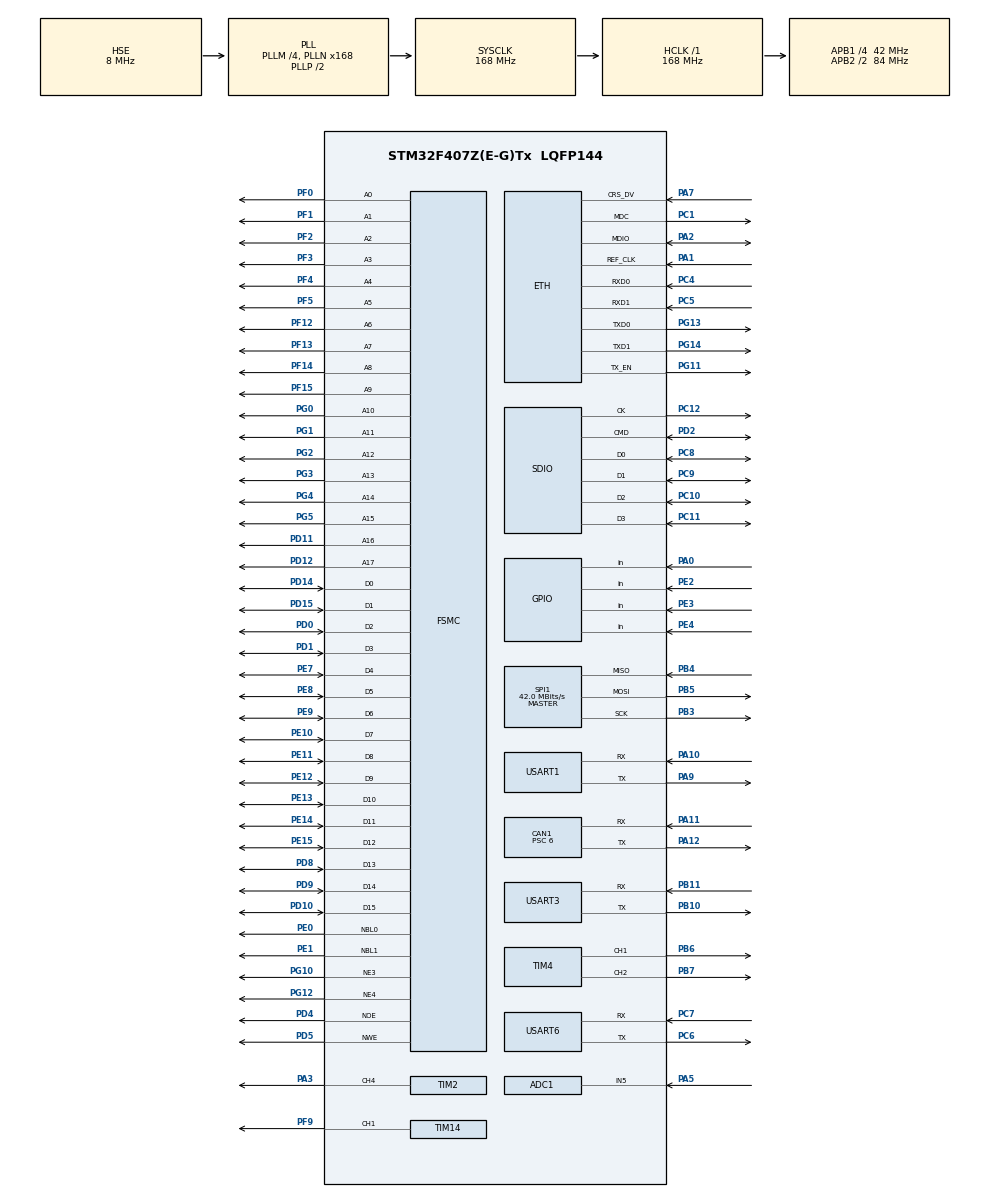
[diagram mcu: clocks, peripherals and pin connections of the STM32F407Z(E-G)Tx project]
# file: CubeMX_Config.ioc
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ADC1.Channel-0\#ChannelRegularConversion=ADC_CHANNEL_5
ADC1.NbrOfConversionFlag=1
ADC1.Rank-0\#ChannelRegularConversion=1
ADC1.SamplingTime-0\#ChannelRegularConversion=ADC_SAMPLETIME_3CYCLES
ADC1.master=1
CAN1.BS1=CAN_BS1_7TQ
CAN1.BS2=CAN_BS2_6TQ
CAN1.CalculateTimeQuantum=142.85714285714286
CAN1.Prescaler=6
ETH.MediaInterface=ETH_MEDIA_INTERFACE_RMII
FSMC.AddressSetupTime3=0
FSMC.BusTurnAroundDuration3=0
FSMC.BusTurnAroundDuration4=0
FSMC.DataSetupTime3=8
FSMC.DataSetupTime4=24
FSMC.ExtendedAddressSetupTime3=0
FSMC.ExtendedAddressSetupTime4=8
FSMC.ExtendedBusTurnAroundDuration3=0
FSMC.ExtendedBusTurnAroundDuration4=0
FSMC.ExtendedDataSetupTime3=8
FSMC.ExtendedDataSetupTime4=8
FSMC.ExtendedMode3=FSMC_EXTENDED_MODE_ENABLE
FSMC.ExtendedMode4=FSMC_EXTENDED_MODE_ENABLE
FSMC.WriteOperation3=FSMC_WRITE_OPERATION_ENABLE
FSMC.WriteOperation4=FSMC_WRITE_OPERATION_ENABLE
Mcu.Family=STM32F4
Mcu.Name=STM32F407Z(E-G)Tx
Mcu.Package=LQFP144
NVIC.PriorityGroup=NVIC_PRIORITYGROUP_4
NVIC.SPI1_IRQn=true\:0\:0\:false\:false\:true\:true\:true
NVIC.USART1_IRQn=true\:0\:0\:false\:false\:true\:true\:true
PA0-WKUP.GPIO_PuPd=GPIO_PULLDOWN
PA0-WKUP.Signal=GPIO_Input
PA1.Mode=RMII
PA1.Signal=ETH_REF_CLK
PA10.Mode=Asynchronous
PA10.Signal=USART1_RX
PA11.GPIO_PuPd=GPIO_PULLUP
PA11.Mode=Master
PA11.Signal=CAN1_RX
PA12.GPIO_PuPd=GPIO_PULLUP
PA12.Mode=Master
PA12.Signal=CAN1_TX
PA13.Mode=Serial_Wire
PA13.Signal=SYS_JTMS-SWDIO
PA14.Mode=Serial_Wire
PA14.Signal=SYS_JTCK-SWCLK
PA2.Mode=RMII
PA2.Signal=ETH_MDIO
PA3.Signal=S_TIM2_CH4
PA5.Signal=ADCx_IN5
PA7.Mode=RMII
PA7.Signal=ETH_CRS_DV
PA9.Mode=Asynchronous
PA9.Signal=USART1_TX
PB10.Mode=Asynchronous
PB10.Signal=USART3_TX
PB11.Mode=Asynchronous
PB11.Signal=USART3_RX
PB3.Mode=Full_Duplex_Master
PB3.Signal=SPI1_SCK
PB4.Mode=Full_Duplex_Master
PB4.Signal=SPI1_MISO
PB5.Mode=Full_Duplex_Master
PB5.Signal=SPI1_MOSI
PB6.Signal=S_TIM4_CH1
PB7.Signal=S_TIM4_CH2
PC1.Mode=RMII
PC1.Signal=ETH_MDC
PC10.Mode=SD_4_bits_Wide_bus
PC10.Signal=SDIO_D2
PC11.Mode=SD_4_bits_Wide_bus
PC11.Signal=SDIO_D3
PC12.Mode=SD_4_bits_Wide_bus
PC12.Signal=SDIO_CK
PC14-OSC32_IN.Mode=LSE-External-Oscillator
PC14-OSC32_IN.Signal=RCC_OSC32_IN
PC15-OSC32_OUT.Mode=LSE-External-Oscillator
PC15-OSC32_OUT.Signal=RCC_OSC32_OUT
PC4.Mode=RMII
PC4.Signal=ETH_RXD0
PC5.Mode=RMII
PC5.Signal=ETH_RXD1
PC6.Mode=Asynchronous
PC6.Signal=USART6_TX
PC7.Mode=Asynchronous
PC7.Signal=USART6_RX
PC8.Mode=SD_4_bits_Wide_bus
PC8.Signal=SDIO_D0
PC9.Mode=SD_4_bits_Wide_bus
PC9.Signal=SDIO_D1
PD0.Signal=FSMC_D2_DA2
PD1.Signal=FSMC_D3_DA3
PD10.Signal=FSMC_D15_DA15
PD11.Signal=FSMC_A16_CLE
PD12.Signal=FSMC_A17_ALE
PD14.Signal=FSMC_D0_DA0
PD15.Signal=FSMC_D1_DA1
PD2.Mode=SD_4_bits_Wide_bus
PD2.Signal=SDIO_CMD
PD4.Signal=FSMC_NOE
PD5.Signal=FSMC_NWE
PD8.Signal=FSMC_D13_DA13
PD9.Signal=FSMC_D14_DA14
PE0.Signal=FSMC_NBL0
PE1.Signal=FSMC_NBL1
PE10.Signal=FSMC_D7_DA7
PE11.Signal=FSMC_D8_DA8
PE12.Signal=FSMC_D9_DA9
PE13.Signal=FSMC_D10_DA10
PE14.Signal=FSMC_D11_DA11
PE15.Signal=FSMC_D12_DA12
PE2.GPIO_PuPd=GPIO_PULLUP
PE2.Signal=GPIO_Input
PE3.GPIO_PuPd=GPIO_PULLUP
PE3.Signal=GPIO_Input
PE4.GPIO_PuPd=GPIO_PULLUP
PE4.Signal=GPIO_Input
PE7.Signal=FSMC_D4_DA4
PE8.Signal=FSMC_D5_DA5
PE9.Signal=FSMC_D6_DA6
PF0.Signal=FSMC_A0
PF1.Signal=FSMC_A1
PF12.Signal=FSMC_A6
PF13.Signal=FSMC_A7
PF14.Signal=FSMC_A8
PF15.Signal=FSMC_A9
PF2.Signal=FSMC_A2
PF3.Signal=FSMC_A3
PF4.Signal=FSMC_A4
PF5.Signal=FSMC_A5
PF9.Signal=S_TIM14_CH1
PG0.Signal=FSMC_A10
PG1.Signal=FSMC_A11
PG10.Mode=NorPsramChipSelect3_3
PG10.Signal=FSMC_NE3
PG11.Mode=RMII
PG11.Signal=ETH_TX_EN
PG12.Mode=NorPsramChipSelect4_4
PG12.Signal=FSMC_NE4
PG13.Mode=RMII
PG13.Signal=ETH_TXD0
PG14.Mode=RMII
PG14.Signal=ETH_TXD1
PG2.Signal=FSMC_A12
PG3.Signal=FSMC_A13
PG4.Signal=FSMC_A14
PG5.Signal=FSMC_A15
PH0-OSC_IN.Mode=HSE-External-Oscillator
PH0-OSC_IN.Signal=RCC_OSC_IN
PH1-OSC_OUT.Mode=HSE-External-Oscillator
PH1-OSC_OUT.Signal=RCC_OSC_OUT
ProjectManager.HeapSize=0x200
ProjectManager.StackSize=0x400
ProjectManager.TargetToolchain=MDK-ARM V5
RCC.48MHZClocksFreq_Value=48000000
RCC.AHBFreq_Value=168000000
RCC.APB1CLKDivider=RCC_HCLK_DIV4
RCC.APB1Freq_Value=42000000
RCC.APB1TimFreq_Value=84000000
RCC.APB2CLKDivider=RCC_HCLK_DIV2
RCC.APB2Freq_Value=84000000
RCC.APB2TimFreq_Value=168000000
RCC.CortexFreq_Value=168000000
RCC.HCLKFreq_Value=168000000
RCC.HSE_VALUE=8000000
RCC.HSI_VALUE=16000000
RCC.PLLM=4
RCC.PLLN=168
RCC.PLLQ=7
RCC.PLLSourceVirtual=RCC_PLLSOURCE_HSE
RCC.RCC_RTC_Clock_Source=RCC_RTCCLKSOURCE_LSE
RCC.RCC_RTC_Clock_SourceVirtual=RCC_RTCCLKSOURCE_LSE
RCC.SYSCLKFreq_VALUE=168000000
RCC.SYSCLKSource=RCC_SYSCLKSOURCE_PLLCLK
RCC.VCOOutputFreq_Value=336000000
SH.ADCx_IN5.0=ADC1_IN5,IN5
SH.FSMC_A0.0=FSMC_A0,18b-a4
SH.FSMC_A0.1=FSMC_A0,18b-a3
SH.FSMC_A1.0=FSMC_A1,18b-a4
SH.FSMC_A1.1=FSMC_A1,18b-a3
SH.FSMC_A10.0=FSMC_A10,18b-a4
SH.FSMC_A10.1=FSMC_A10,18b-a3
SH.FSMC_A11.0=FSMC_A11,18b-a4
SH.FSMC_A11.1=FSMC_A11,18b-a3
SH.FSMC_A12.0=FSMC_A12,18b-a4
SH.FSMC_A12.1=FSMC_A12,18b-a3
SH.FSMC_A13.0=FSMC_A13,18b-a4
SH.FSMC_A13.1=FSMC_A13,18b-a3
SH.FSMC_A14.0=FSMC_A14,18b-a4
SH.FSMC_A14.1=FSMC_A14,18b-a3
SH.FSMC_A15.0=FSMC_A15,18b-a4
SH.FSMC_A15.1=FSMC_A15,18b-a3
SH.FSMC_A16_CLE.0=FSMC_A16,18b-a4
SH.FSMC_A16_CLE.1=FSMC_A16,18b-a3
SH.FSMC_A17_ALE.0=FSMC_A17,18b-a4
SH.FSMC_A17_ALE.1=FSMC_A17,18b-a3
SH.FSMC_A2.0=FSMC_A2,18b-a4
SH.FSMC_A2.1=FSMC_A2,18b-a3
SH.FSMC_A3.0=FSMC_A3,18b-a4
SH.FSMC_A3.1=FSMC_A3,18b-a3
SH.FSMC_A4.0=FSMC_A4,18b-a4
SH.FSMC_A4.1=FSMC_A4,18b-a3
SH.FSMC_A5.0=FSMC_A5,18b-a4
SH.FSMC_A5.1=FSMC_A5,18b-a3
SH.FSMC_A6.0=FSMC_A6,18b-a4
SH.FSMC_A6.1=FSMC_A6,18b-a3
SH.FSMC_A7.0=FSMC_A7,18b-a4
SH.FSMC_A7.1=FSMC_A7,18b-a3
SH.FSMC_A8.0=FSMC_A8,18b-a4
SH.FSMC_A8.1=FSMC_A8,18b-a3
SH.FSMC_A9.0=FSMC_A9,18b-a4
SH.FSMC_A9.1=FSMC_A9,18b-a3
SH.FSMC_D0_DA0.0=FSMC_D0,16b-d4
SH.FSMC_D0_DA0.1=FSMC_D0,16b-d3
SH.FSMC_D10_DA10.0=FSMC_D10,16b-d4
SH.FSMC_D10_DA10.1=FSMC_D10,16b-d3
SH.FSMC_D11_DA11.0=FSMC_D11,16b-d4
SH.FSMC_D11_DA11.1=FSMC_D11,16b-d3
SH.FSMC_D12_DA12.0=FSMC_D12,16b-d4
SH.FSMC_D12_DA12.1=FSMC_D12,16b-d3
SH.FSMC_D13_DA13.0=FSMC_D13,16b-d4
SH.FSMC_D13_DA13.1=FSMC_D13,16b-d3
SH.FSMC_D14_DA14.0=FSMC_D14,16b-d4
SH.FSMC_D14_DA14.1=FSMC_D14,16b-d3
SH.FSMC_D15_DA15.0=FSMC_D15,16b-d4
SH.FSMC_D15_DA15.1=FSMC_D15,16b-d3
SH.FSMC_D1_DA1.0=FSMC_D1,16b-d4
SH.FSMC_D1_DA1.1=FSMC_D1,16b-d3
SH.FSMC_D2_DA2.0=FSMC_D2,16b-d4
SH.FSMC_D2_DA2.1=FSMC_D2,16b-d3
SH.FSMC_D3_DA3.0=FSMC_D3,16b-d4
SH.FSMC_D3_DA3.1=FSMC_D3,16b-d3
SH.FSMC_D4_DA4.0=FSMC_D4,16b-d4
SH.FSMC_D4_DA4.1=FSMC_D4,16b-d3
SH.FSMC_D5_DA5.0=FSMC_D5,16b-d4
SH.FSMC_D5_DA5.1=FSMC_D5,16b-d3
SH.FSMC_D6_DA6.0=FSMC_D6,16b-d4
SH.FSMC_D6_DA6.1=FSMC_D6,16b-d3
SH.FSMC_D7_DA7.0=FSMC_D7,16b-d4
SH.FSMC_D7_DA7.1=FSMC_D7,16b-d3
SH.FSMC_D8_DA8.0=FSMC_D8,16b-d4
SH.FSMC_D8_DA8.1=FSMC_D8,16b-d3
SH.FSMC_D9_DA9.0=FSMC_D9,16b-d4
SH.FSMC_D9_DA9.1=FSMC_D9,16b-d3
SH.FSMC_NBL0.0=FSMC_NBL0,2ByteEnable3
SH.FSMC_NBL1.0=FSMC_NBL1,2ByteEnable3
SH.FSMC_NOE.0=FSMC_NOE,Sram3
SH.FSMC_NOE.1=FSMC_NOE,Sram4
SH.FSMC_NWE.0=FSMC_NWE,Sram3
SH.FSMC_NWE.1=FSMC_NWE,Sram4
SH.S_TIM14_CH1.0=TIM14_CH1,PWM Generation1 CH1
SH.S_TIM2_CH4.0=TIM2_CH4,PWM Generation4 CH4
SH.S_TIM4_CH1.0=TIM4_CH1,PWM Generation1 CH1
SH.S_TIM4_CH2.0=TIM4_CH2,PWM Generation2 CH2
SPI1.CalculateBaudRate=42.0 MBits/s
SPI1.Direction=SPI_DIRECTION_2LINES
SPI1.Mode=SPI_MODE_MASTER
SPI1.VirtualType=VM_MASTER
TIM14.Channel=TIM_CHANNEL_1
TIM2.Channel-PWM\ Generation4\ CH4=TIM_CHANNEL_4
TIM4.Channel-PWM\ Generation1\ CH1=TIM_CHANNEL_1
TIM4.Channel-PWM\ Generation2\ CH2=TIM_CHANNEL_2
USART1.VirtualMode=VM_ASYNC
USART3.VirtualMode=VM_ASYNC
USART6.VirtualMode=VM_ASYNC
VP_CRC_VS_CRC.Mode=CRC_Activate
VP_IWDG_VS_IWDG.Mode=IWDG_Activate
VP_RTC_VS_RTC_Activate.Mode=RTC_Enabled
VP_TIM11_VS_ClockSourceINT.Mode=Enable_Timer
VP_TIM13_VS_ClockSourceINT.Mode=Enable_Timer
VP_TIM14_VS_ClockSourceINT.Mode=Enable_Timer
VP_TIM2_VS_ClockSourceINT.Mode=Internal
VP_TIM4_VS_ClockSourceINT.Mode=Internal
board=custom

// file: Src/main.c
/* USER CODE BEGIN Header */
/**
  ******************************************************************************
  * @file           : main.c
  * @brief          : Main program body
  ******************************************************************************
  ** This notice applies to any and all portions of this file
  * that are not between comment pairs USER CODE BEGIN and
  * USER CODE END. Other portions of this file, whether
  * inserted by the user or by software development tools
  * are owned by their respective copyright owners.
  *
  * COPYRIGHT(c) 2018 STMicroelectronics
  *
  * Redistribution and use in source and binary forms, with or without modification,
  * are permitted provided that the following conditions are met:
  *   1. Redistributions of source code must retain the above copyright notice,
  *      this list of conditions and the following disclaimer.
  *   2. Redistributions in binary form must reproduce the above copyright notice,
  *      this list of conditions and the following disclaimer in the documentation
  *      and/or other materials provided with the distribution.
  *   3. Neither the name of STMicroelectronics nor the names of its contributors
  *      may be used to endorse or promote products derived from this software
  *      without specific prior written permission.
  *
  * THIS SOFTWARE IS PROVIDED BY THE COPYRIGHT HOLDERS AND CONTRIBUTORS "AS IS"
  * AND ANY EXPRESS OR IMPLIED WARRANTIES, INCLUDING, BUT NOT LIMITED TO, THE
  * IMPLIED WARRANTIES OF MERCHANTABILITY AND FITNESS FOR A PARTICULAR PURPOSE ARE
  * DISCLAIMED. IN NO EVENT SHALL THE COPYRIGHT HOLDER OR CONTRIBUTORS BE LIABLE
  * FOR ANY DIRECT, INDIRECT, INCIDENTAL, SPECIAL, EXEMPLARY, OR CONSEQUENTIAL
  * DAMAGES (INCLUDING, BUT NOT LIMITED TO, PROCUREMENT OF SUBSTITUTE GOODS OR
  * SERVICES; LOSS OF USE, DATA, OR PROFITS; OR BUSINESS INTERRUPTION) HOWEVER
  * CAUSED AND ON ANY THEORY OF LIABILITY, WHETHER IN CONTRACT, STRICT LIABILITY,
  * OR TORT (INCLUDING NEGLIGENCE OR OTHERWISE) ARISING IN ANY WAY OUT OF THE USE
  * OF THIS SOFTWARE, EVEN IF ADVISED OF THE POSSIBILITY OF SUCH DAMAGE.
  *
  ******************************************************************************
  */
/* USER CODE END Header */

#include "main.h"

ADC_HandleTypeDef hadc1;

CAN_HandleTypeDef hcan1;

CRC_HandleTypeDef hcrc;

ETH_HandleTypeDef heth;

IWDG_HandleTypeDef hiwdg;

RTC_HandleTypeDef hrtc;

SD_HandleTypeDef hsd;

SPI_HandleTypeDef hspi1;

TIM_HandleTypeDef htim2;
TIM_HandleTypeDef htim4;
TIM_HandleTypeDef htim11;
TIM_HandleTypeDef htim13;
TIM_HandleTypeDef htim14;

UART_HandleTypeDef huart1;
UART_HandleTypeDef huart3;
UART_HandleTypeDef huart6;

SRAM_HandleTypeDef hsram3;
SRAM_HandleTypeDef hsram4;

/* USER CODE BEGIN PV */
/* Private variables ---------------------------------------------------------*/

/* USER CODE END PV */

void SystemClock_Config(void);
static void MX_GPIO_Init(void);
static void MX_USART1_UART_Init(void);
static void MX_SPI1_Init(void);
static void MX_ETH_Init(void);
static void MX_USART3_UART_Init(void);
static void MX_ADC1_Init(void);
static void MX_RTC_Init(void);
static void MX_IWDG_Init(void);
static void MX_TIM14_Init(void);
static void MX_TIM13_Init(void);
static void MX_TIM11_Init(void);
static void MX_SDIO_SD_Init(void);
static void MX_TIM2_Init(void);
static void MX_CRC_Init(void);
static void MX_FSMC_Init(void);
static void MX_CAN1_Init(void);
static void MX_TIM4_Init(void);
static void MX_USART6_UART_Init(void);
/* USER CODE BEGIN PFP */
/* Private function prototypes -----------------------------------------------*/

/* USER CODE END PFP */

int main(void)
{

  /* MCU Configuration--------------------------------------------------------*/

  /* Reset of all peripherals, Initializes the Flash interface and the Systick. */
  HAL_Init();

  /* Configure the system clock */
  SystemClock_Config();

  /* Initialize all configured peripherals */
  MX_GPIO_Init();
  MX_USART1_UART_Init();
  MX_SPI1_Init();
  MX_ETH_Init();
  MX_USART3_UART_Init();
  MX_ADC1_Init();
  MX_RTC_Init();
  MX_IWDG_Init();
  MX_TIM14_Init();
  MX_TIM13_Init();
  MX_TIM11_Init();
  MX_SDIO_SD_Init();
  MX_TIM2_Init();
  MX_CRC_Init();
  MX_FSMC_Init();
  MX_CAN1_Init();
  MX_TIM4_Init();
  MX_USART6_UART_Init();

  /* Infinite loop */
  while (1)
  {

  }
}

void SystemClock_Config(void)
{
  RCC_OscInitTypeDef RCC_OscInitStruct = {0};
  RCC_ClkInitTypeDef RCC_ClkInitStruct = {0};
  RCC_PeriphCLKInitTypeDef PeriphClkInitStruct = {0};

  /**Configure the main internal regulator output voltage
  */
  __HAL_RCC_PWR_CLK_ENABLE();
  __HAL_PWR_VOLTAGESCALING_CONFIG(PWR_REGULATOR_VOLTAGE_SCALE1);
  /**Initializes the CPU, AHB and APB busses clocks
  */
  RCC_OscInitStruct.OscillatorType = RCC_OSCILLATORTYPE_LSI|RCC_OSCILLATORTYPE_HSE
                              |RCC_OSCILLATORTYPE_LSE;
  RCC_OscInitStruct.HSEState = RCC_HSE_ON;
  RCC_OscInitStruct.LSEState = RCC_LSE_ON;
  RCC_OscInitStruct.LSIState = RCC_LSI_ON;
  RCC_OscInitStruct.PLL.PLLState = RCC_PLL_ON;
  RCC_OscInitStruct.PLL.PLLSource = RCC_PLLSOURCE_HSE;
  RCC_OscInitStruct.PLL.PLLM = 4;
  RCC_OscInitStruct.PLL.PLLN = 168;
  RCC_OscInitStruct.PLL.PLLP = RCC_PLLP_DIV2;
  RCC_OscInitStruct.PLL.PLLQ = 7;
  if (HAL_RCC_OscConfig(&RCC_OscInitStruct) != HAL_OK)
  {
    Error_Handler();
  }
  /**Initializes the CPU, AHB and APB busses clocks
  */
  RCC_ClkInitStruct.ClockType = RCC_CLOCKTYPE_HCLK|RCC_CLOCKTYPE_SYSCLK
                              |RCC_CLOCKTYPE_PCLK1|RCC_CLOCKTYPE_PCLK2;
  RCC_ClkInitStruct.SYSCLKSource = RCC_SYSCLKSOURCE_PLLCLK;
  RCC_ClkInitStruct.AHBCLKDivider = RCC_SYSCLK_DIV1;
  RCC_ClkInitStruct.APB1CLKDivider = RCC_HCLK_DIV4;
  RCC_ClkInitStruct.APB2CLKDivider = RCC_HCLK_DIV2;

  if (HAL_RCC_ClockConfig(&RCC_ClkInitStruct, FLASH_LATENCY_5) != HAL_OK)
  {
    Error_Handler();
  }
  PeriphClkInitStruct.PeriphClockSelection = RCC_PERIPHCLK_RTC;
  PeriphClkInitStruct.RTCClockSelection = RCC_RTCCLKSOURCE_LSE;
  if (HAL_RCCEx_PeriphCLKConfig(&PeriphClkInitStruct) != HAL_OK)
  {
    Error_Handler();
  }
}

static void MX_ADC1_Init(void)
{

  ADC_ChannelConfTypeDef sConfig = {0};

  /**Configure the global features of the ADC (Clock, Resolution, Data Alignment and number of conversion)
  */
  hadc1.Instance = ADC1;
  hadc1.Init.ClockPrescaler = ADC_CLOCK_SYNC_PCLK_DIV4;
  hadc1.Init.Resolution = ADC_RESOLUTION_12B;
  hadc1.Init.ScanConvMode = DISABLE;
  hadc1.Init.ContinuousConvMode = DISABLE;
  hadc1.Init.DiscontinuousConvMode = DISABLE;
  hadc1.Init.ExternalTrigConvEdge = ADC_EXTERNALTRIGCONVEDGE_NONE;
  hadc1.Init.ExternalTrigConv = ADC_SOFTWARE_START;
  hadc1.Init.DataAlign = ADC_DATAALIGN_RIGHT;
  hadc1.Init.NbrOfConversion = 1;
  hadc1.Init.DMAContinuousRequests = DISABLE;
  hadc1.Init.EOCSelection = ADC_EOC_SINGLE_CONV;
  if (HAL_ADC_Init(&hadc1) != HAL_OK)
  {
    Error_Handler();
  }
  /**Configure for the selected ADC regular channel its corresponding rank in the sequencer and its sample time.
  */
  sConfig.Channel = ADC_CHANNEL_5;
  sConfig.Rank = 1;
  sConfig.SamplingTime = ADC_SAMPLETIME_3CYCLES;
  if (HAL_ADC_ConfigChannel(&hadc1, &sConfig) != HAL_OK)
  {
    Error_Handler();
  }

}

static void MX_CAN1_Init(void)
{

  hcan1.Instance = CAN1;
  hcan1.Init.Prescaler = 6;
  hcan1.Init.Mode = CAN_MODE_NORMAL;
  hcan1.Init.SyncJumpWidth = CAN_SJW_1TQ;
  hcan1.Init.TimeSeg1 = CAN_BS1_7TQ;
  hcan1.Init.TimeSeg2 = CAN_BS2_6TQ;
  hcan1.Init.TimeTriggeredMode = DISABLE;
  hcan1.Init.AutoBusOff = DISABLE;
  hcan1.Init.AutoWakeUp = DISABLE;
  hcan1.Init.AutoRetransmission = DISABLE;
  hcan1.Init.ReceiveFifoLocked = DISABLE;
  hcan1.Init.TransmitFifoPriority = DISABLE;
  if (HAL_CAN_Init(&hcan1) != HAL_OK)
  {
    Error_Handler();
  }

}

static void MX_CRC_Init(void)
{

  hcrc.Instance = CRC;
  if (HAL_CRC_Init(&hcrc) != HAL_OK)
  {
    Error_Handler();
  }

}

static void MX_ETH_Init(void)
{

   uint8_t MACAddr[6] ;

  heth.Instance = ETH;
  heth.Init.AutoNegotiation = ETH_AUTONEGOTIATION_ENABLE;
  heth.Init.PhyAddress = LAN8742A_PHY_ADDRESS;
  MACAddr[0] = 0x00;
  MACAddr[1] = 0x80;
  MACAddr[2] = 0xE1;
  MACAddr[3] = 0x00;
  MACAddr[4] = 0x00;
  MACAddr[5] = 0x00;
  heth.Init.MACAddr = &MACAddr[0];
  heth.Init.RxMode = ETH_RXPOLLING_MODE;
  heth.Init.ChecksumMode = ETH_CHECKSUM_BY_HARDWARE;
  heth.Init.MediaInterface = ETH_MEDIA_INTERFACE_RMII;

  if (HAL_ETH_Init(&heth) != HAL_OK)
  {
    Error_Handler();
  }

}

static void MX_IWDG_Init(void)
{

  hiwdg.Instance = IWDG;
  hiwdg.Init.Prescaler = IWDG_PRESCALER_4;
  hiwdg.Init.Reload = 4095;
  if (HAL_IWDG_Init(&hiwdg) != HAL_OK)
  {
    Error_Handler();
  }

}

static void MX_RTC_Init(void)
{

  /**Initialize RTC Only
  */
  hrtc.Instance = RTC;
  hrtc.Init.HourFormat = RTC_HOURFORMAT_24;
  hrtc.Init.AsynchPrediv = 127;
  hrtc.Init.SynchPrediv = 255;
  hrtc.Init.OutPut = RTC_OUTPUT_DISABLE;
  hrtc.Init.OutPutPolarity = RTC_OUTPUT_POLARITY_HIGH;
  hrtc.Init.OutPutType = RTC_OUTPUT_TYPE_OPENDRAIN;
  if (HAL_RTC_Init(&hrtc) != HAL_OK)
  {
    Error_Handler();
  }

}

static void MX_SDIO_SD_Init(void)
{

  hsd.Instance = SDIO;
  hsd.Init.ClockEdge = SDIO_CLOCK_EDGE_RISING;
  hsd.Init.ClockBypass = SDIO_CLOCK_BYPASS_DISABLE;
  hsd.Init.ClockPowerSave = SDIO_CLOCK_POWER_SAVE_DISABLE;
  hsd.Init.BusWide = SDIO_BUS_WIDE_1B;
  hsd.Init.HardwareFlowControl = SDIO_HARDWARE_FLOW_CONTROL_DISABLE;
  hsd.Init.ClockDiv = 0;
  if (HAL_SD_Init(&hsd) != HAL_OK)
  {
    Error_Handler();
  }
  if (HAL_SD_ConfigWideBusOperation(&hsd, SDIO_BUS_WIDE_4B) != HAL_OK)
  {
    Error_Handler();
  }

}

static void MX_SPI1_Init(void)
{

  /* SPI1 parameter configuration*/
  hspi1.Instance = SPI1;
  hspi1.Init.Mode = SPI_MODE_MASTER;
  hspi1.Init.Direction = SPI_DIRECTION_2LINES;
  hspi1.Init.DataSize = SPI_DATASIZE_8BIT;
  hspi1.Init.CLKPolarity = SPI_POLARITY_LOW;
  hspi1.Init.CLKPhase = SPI_PHASE_1EDGE;
  hspi1.Init.NSS = SPI_NSS_SOFT;
  hspi1.Init.BaudRatePrescaler = SPI_BAUDRATEPRESCALER_2;
  hspi1.Init.FirstBit = SPI_FIRSTBIT_MSB;
  hspi1.Init.TIMode = SPI_TIMODE_DISABLE;
  hspi1.Init.CRCCalculation = SPI_CRCCALCULATION_DISABLE;
  hspi1.Init.CRCPolynomial = 10;
  if (HAL_SPI_Init(&hspi1) != HAL_OK)
  {
    Error_Handler();
  }

}

static void MX_TIM2_Init(void)
{

  TIM_ClockConfigTypeDef sClockSourceConfig = {0};
  TIM_MasterConfigTypeDef sMasterConfig = {0};
  TIM_OC_InitTypeDef sConfigOC = {0};

  htim2.Instance = TIM2;
  htim2.Init.Prescaler = 0;
  htim2.Init.CounterMode = TIM_COUNTERMODE_UP;
  htim2.Init.Period = 0;
  htim2.Init.ClockDivision = TIM_CLOCKDIVISION_DIV1;
  if (HAL_TIM_Base_Init(&htim2) != HAL_OK)
  {
    Error_Handler();
  }
  sClockSourceConfig.ClockSource = TIM_CLOCKSOURCE_INTERNAL;
  if (HAL_TIM_ConfigClockSource(&htim2, &sClockSourceConfig) != HAL_OK)
  {
    Error_Handler();
  }
  if (HAL_TIM_PWM_Init(&htim2) != HAL_OK)
  {
    Error_Handler();
  }
  sMasterConfig.MasterOutputTrigger = TIM_TRGO_RESET;
  sMasterConfig.MasterSlaveMode = TIM_MASTERSLAVEMODE_DISABLE;
  if (HAL_TIMEx_MasterConfigSynchronization(&htim2, &sMasterConfig) != HAL_OK)
  {
    Error_Handler();
  }
  sConfigOC.OCMode = TIM_OCMODE_PWM1;
  sConfigOC.Pulse = 0;
  sConfigOC.OCPolarity = TIM_OCPOLARITY_HIGH;
  sConfigOC.OCFastMode = TIM_OCFAST_DISABLE;
  if (HAL_TIM_PWM_ConfigChannel(&htim2, &sConfigOC, TIM_CHANNEL_4) != HAL_OK)
  {
    Error_Handler();
  }
  HAL_TIM_MspPostInit(&htim2);

}

static void MX_TIM4_Init(void)
{

  TIM_ClockConfigTypeDef sClockSourceConfig = {0};
  TIM_MasterConfigTypeDef sMasterConfig = {0};
  TIM_OC_InitTypeDef sConfigOC = {0};

  htim4.Instance = TIM4;
  htim4.Init.Prescaler = 0;
  htim4.Init.CounterMode = TIM_COUNTERMODE_UP;
  htim4.Init.Period = 0;
  htim4.Init.ClockDivision = TIM_CLOCKDIVISION_DIV1;
  if (HAL_TIM_Base_Init(&htim4) != HAL_OK)
  {
    Error_Handler();
  }
  sClockSourceConfig.ClockSource = TIM_CLOCKSOURCE_INTERNAL;
  if (HAL_TIM_ConfigClockSource(&htim4, &sClockSourceConfig) != HAL_OK)
  {
    Error_Handler();
  }
  if (HAL_TIM_PWM_Init(&htim4) != HAL_OK)
  {
    Error_Handler();
  }
  sMasterConfig.MasterOutputTrigger = TIM_TRGO_RESET;
  sMasterConfig.MasterSlaveMode = TIM_MASTERSLAVEMODE_DISABLE;
  if (HAL_TIMEx_MasterConfigSynchronization(&htim4, &sMasterConfig) != HAL_OK)
  {
    Error_Handler();
  }
  sConfigOC.OCMode = TIM_OCMODE_PWM1;
  sConfigOC.Pulse = 0;
  sConfigOC.OCPolarity = TIM_OCPOLARITY_HIGH;
  sConfigOC.OCFastMode = TIM_OCFAST_DISABLE;
  if (HAL_TIM_PWM_ConfigChannel(&htim4, &sConfigOC, TIM_CHANNEL_1) != HAL_OK)
  {
    Error_Handler();
  }
  if (HAL_TIM_PWM_ConfigChannel(&htim4, &sConfigOC, TIM_CHANNEL_2) != HAL_OK)
  {
    Error_Handler();
  }
  HAL_TIM_MspPostInit(&htim4);

}

static void MX_TIM11_Init(void)
{

  htim11.Instance = TIM11;
  htim11.Init.Prescaler = 0;
  htim11.Init.CounterMode = TIM_COUNTERMODE_UP;
  htim11.Init.Period = 0;
  htim11.Init.ClockDivision = TIM_CLOCKDIVISION_DIV1;
  if (HAL_TIM_Base_Init(&htim11) != HAL_OK)
  {
    Error_Handler();
  }

}

static void MX_TIM13_Init(void)
{

  htim13.Instance = TIM13;
  htim13.Init.Prescaler = 0;
  htim13.Init.CounterMode = TIM_COUNTERMODE_UP;
  htim13.Init.Period = 0;
  htim13.Init.ClockDivision = TIM_CLOCKDIVISION_DIV1;
  if (HAL_TIM_Base_Init(&htim13) != HAL_OK)
  {
    Error_Handler();
  }

}

static void MX_TIM14_Init(void)
{

  TIM_OC_InitTypeDef sConfigOC = {0};

  htim14.Instance = TIM14;
  htim14.Init.Prescaler = 0;
  htim14.Init.CounterMode = TIM_COUNTERMODE_UP;
  htim14.Init.Period = 0;
  htim14.Init.ClockDivision = TIM_CLOCKDIVISION_DIV1;
  if (HAL_TIM_Base_Init(&htim14) != HAL_OK)
  {
    Error_Handler();
  }
  if (HAL_TIM_PWM_Init(&htim14) != HAL_OK)
  {
    Error_Handler();
  }
  sConfigOC.OCMode = TIM_OCMODE_PWM1;
  sConfigOC.Pulse = 0;
  sConfigOC.OCPolarity = TIM_OCPOLARITY_HIGH;
  sConfigOC.OCFastMode = TIM_OCFAST_DISABLE;
  if (HAL_TIM_PWM_ConfigChannel(&htim14, &sConfigOC, TIM_CHANNEL_1) != HAL_OK)
  {
    Error_Handler();
  }
  HAL_TIM_MspPostInit(&htim14);

}

static void MX_USART1_UART_Init(void)
{

  huart1.Instance = USART1;
  huart1.Init.BaudRate = 115200;
  huart1.Init.WordLength = UART_WORDLENGTH_8B;
  huart1.Init.StopBits = UART_STOPBITS_1;
  huart1.Init.Parity = UART_PARITY_NONE;
  huart1.Init.Mode = UART_MODE_TX_RX;
  huart1.Init.HwFlowCtl = UART_HWCONTROL_NONE;
  huart1.Init.OverSampling = UART_OVERSAMPLING_16;
  if (HAL_UART_Init(&huart1) != HAL_OK)
  {
    Error_Handler();
  }

}

static void MX_USART3_UART_Init(void)
{

  huart3.Instance = USART3;
  huart3.Init.BaudRate = 115200;
  huart3.Init.WordLength = UART_WORDLENGTH_8B;
  huart3.Init.StopBits = UART_STOPBITS_1;
  huart3.Init.Parity = UART_PARITY_NONE;
  huart3.Init.Mode = UART_MODE_TX_RX;
  huart3.Init.HwFlowCtl = UART_HWCONTROL_NONE;
  huart3.Init.OverSampling = UART_OVERSAMPLING_16;
  if (HAL_UART_Init(&huart3) != HAL_OK)
  {
    Error_Handler();
  }

}

static void MX_USART6_UART_Init(void)
{

  huart6.Instance = USART6;
  huart6.Init.BaudRate = 115200;
  huart6.Init.WordLength = UART_WORDLENGTH_8B;
  huart6.Init.StopBits = UART_STOPBITS_1;
  huart6.Init.Parity = UART_PARITY_NONE;
  huart6.Init.Mode = UART_MODE_TX_RX;
  huart6.Init.HwFlowCtl = UART_HWCONTROL_NONE;
  huart6.Init.OverSampling = UART_OVERSAMPLING_16;
  if (HAL_UART_Init(&huart6) != HAL_OK)
  {
    Error_Handler();
  }

}

static void MX_GPIO_Init(void)
{
  GPIO_InitTypeDef GPIO_InitStruct = {0};

  /* GPIO Ports Clock Enable */
  __HAL_RCC_GPIOE_CLK_ENABLE();
  __HAL_RCC_GPIOC_CLK_ENABLE();
  __HAL_RCC_GPIOF_CLK_ENABLE();
  __HAL_RCC_GPIOH_CLK_ENABLE();
  __HAL_RCC_GPIOA_CLK_ENABLE();
  __HAL_RCC_GPIOG_CLK_ENABLE();
  __HAL_RCC_GPIOB_CLK_ENABLE();
  __HAL_RCC_GPIOD_CLK_ENABLE();

  /*Configure GPIO pins : PE2 PE3 PE4 */
  GPIO_InitStruct.Pin = GPIO_PIN_2|GPIO_PIN_3|GPIO_PIN_4;
  GPIO_InitStruct.Mode = GPIO_MODE_INPUT;
  GPIO_InitStruct.Pull = GPIO_PULLUP;
  HAL_GPIO_Init(GPIOE, &GPIO_InitStruct);

  /*Configure GPIO pin : PA0 */
  GPIO_InitStruct.Pin = GPIO_PIN_0;
  GPIO_InitStruct.Mode = GPIO_MODE_INPUT;
  GPIO_InitStruct.Pull = GPIO_PULLDOWN;
  HAL_GPIO_Init(GPIOA, &GPIO_InitStruct);

  /*Configure GPIO pins : PB12 PB13 */
  GPIO_InitStruct.Pin = GPIO_PIN_12|GPIO_PIN_13;
  GPIO_InitStruct.Mode = GPIO_MODE_IT_RISING;
  GPIO_InitStruct.Pull = GPIO_NOPULL;
  HAL_GPIO_Init(GPIOB, &GPIO_InitStruct);

}

/* FSMC initialization function */
static void MX_FSMC_Init(void)
{
  FSMC_NORSRAM_TimingTypeDef Timing;
  FSMC_NORSRAM_TimingTypeDef ExtTiming;

  /** Perform the SRAM3 memory initialization sequence
  */
  hsram3.Instance = FSMC_NORSRAM_DEVICE;
  hsram3.Extended = FSMC_NORSRAM_EXTENDED_DEVICE;
  /* hsram3.Init */
  hsram3.Init.NSBank = FSMC_NORSRAM_BANK3;
  hsram3.Init.DataAddressMux = FSMC_DATA_ADDRESS_MUX_DISABLE;
  hsram3.Init.MemoryType = FSMC_MEMORY_TYPE_SRAM;
  hsram3.Init.MemoryDataWidth = FSMC_NORSRAM_MEM_BUS_WIDTH_16;
  hsram3.Init.BurstAccessMode = FSMC_BURST_ACCESS_MODE_DISABLE;
  hsram3.Init.WaitSignalPolarity = FSMC_WAIT_SIGNAL_POLARITY_LOW;
  hsram3.Init.WrapMode = FSMC_WRAP_MODE_DISABLE;
  hsram3.Init.WaitSignalActive = FSMC_WAIT_TIMING_BEFORE_WS;
  hsram3.Init.WriteOperation = FSMC_WRITE_OPERATION_ENABLE;
  hsram3.Init.WaitSignal = FSMC_WAIT_SIGNAL_DISABLE;
  hsram3.Init.ExtendedMode = FSMC_EXTENDED_MODE_ENABLE;
  hsram3.Init.AsynchronousWait = FSMC_ASYNCHRONOUS_WAIT_DISABLE;
  hsram3.Init.WriteBurst = FSMC_WRITE_BURST_DISABLE;
  hsram3.Init.PageSize = FSMC_PAGE_SIZE_NONE;
  /* Timing */
  Timing.AddressSetupTime = 0;
  Timing.AddressHoldTime = 15;
  Timing.DataSetupTime = 8;
  Timing.BusTurnAroundDuration = 0;
  Timing.CLKDivision = 16;
  Timing.DataLatency = 17;
  Timing.AccessMode = FSMC_ACCESS_MODE_A;
  /* ExtTiming */
  ExtTiming.AddressSetupTime = 0;
  ExtTiming.AddressHoldTime = 15;
  ExtTiming.DataSetupTime = 8;
  ExtTiming.BusTurnAroundDuration = 0;
  ExtTiming.CLKDivision = 16;
  ExtTiming.DataLatency = 17;
  ExtTiming.AccessMode = FSMC_ACCESS_MODE_A;

  if (HAL_SRAM_Init(&hsram3, &Timing, &ExtTiming) != HAL_OK)
  {
    Error_Handler( );
  }

  /** Perform the SRAM4 memory initialization sequence
  */
  hsram4.Instance = FSMC_NORSRAM_DEVICE;
  hsram4.Extended = FSMC_NORSRAM_EXTENDED_DEVICE;
  /* hsram4.Init */
  hsram4.Init.NSBank = FSMC_NORSRAM_BANK4;
  hsram4.Init.DataAddressMux = FSMC_DATA_ADDRESS_MUX_DISABLE;
  hsram4.Init.MemoryType = FSMC_MEMORY_TYPE_SRAM;
  hsram4.Init.MemoryDataWidth = FSMC_NORSRAM_MEM_BUS_WIDTH_16;
  hsram4.Init.BurstAccessMode = FSMC_BURST_ACCESS_MODE_DISABLE;
  hsram4.Init.WaitSignalPolarity = FSMC_WAIT_SIGNAL_POLARITY_LOW;
  hsram4.Init.WrapMode = FSMC_WRAP_MODE_DISABLE;
  hsram4.Init.WaitSignalActive = FSMC_WAIT_TIMING_BEFORE_WS;
  hsram4.Init.WriteOperation = FSMC_WRITE_OPERATION_ENABLE;
  hsram4.Init.WaitSignal = FSMC_WAIT_SIGNAL_DISABLE;
  hsram4.Init.ExtendedMode = FSMC_EXTENDED_MODE_ENABLE;
  hsram4.Init.AsynchronousWait = FSMC_ASYNCHRONOUS_WAIT_DISABLE;
  hsram4.Init.WriteBurst = FSMC_WRITE_BURST_DISABLE;
  hsram4.Init.PageSize = FSMC_PAGE_SIZE_NONE;
  /* Timing */
  Timing.AddressSetupTime = 15;
  Timing.AddressHoldTime = 15;
  Timing.DataSetupTime = 24;
  Timing.BusTurnAroundDuration = 0;
  Timing.CLKDivision = 16;
  Timing.DataLatency = 17;
  Timing.AccessMode = FSMC_ACCESS_MODE_A;
  /* ExtTiming */
  ExtTiming.AddressSetupTime = 8;
  ExtTiming.AddressHoldTime = 15;
  ExtTiming.DataSetupTime = 8;
  ExtTiming.BusTurnAroundDuration = 0;
  ExtTiming.CLKDivision = 16;
  ExtTiming.DataLatency = 17;
  ExtTiming.AccessMode = FSMC_ACCESS_MODE_A;

  if (HAL_SRAM_Init(&hsram4, &Timing, &ExtTiming) != HAL_OK)
  {
    Error_Handler( );
  }

}

void Error_Handler(void)
{
  while(1)
  {
  }
}

/************************ (C) COPYRIGHT STMicroelectronics *****END OF FILE****/
